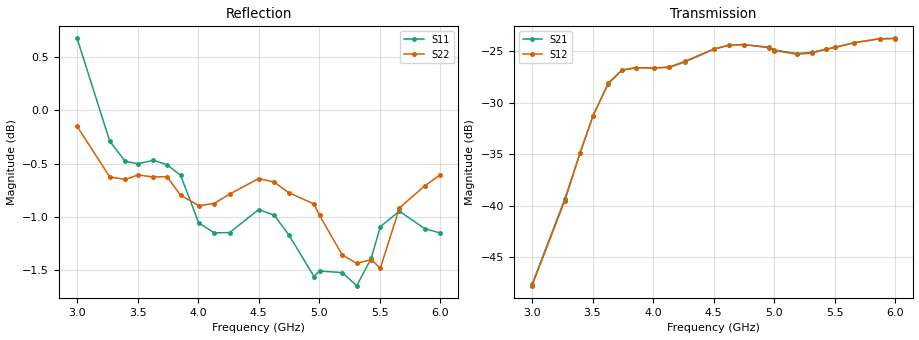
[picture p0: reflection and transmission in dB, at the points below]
!  26/11/2025  15:59:12
! Ref Plane: 0.000 mm
# MHZ S MA R  50
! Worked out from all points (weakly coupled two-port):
!   401 points, 3 GHz to 6 GHz, reference 50 ohm
!   highest |S21| = -23.72 dB at 6 GHz (marker M1); lowest = -47.7 dB at 3 GHz (marker M2)
!   lowest |S11| = -1.6 dB at 5.31 GHz (marker M3), VSWR 10.60, Z = 4.72 + j1.25 ohm
!   |S11| at or under -10 dB: nowhere
!   |S22| runs from -1.5 to -0.1 dB; largest |S21 - S12| = 0.0027
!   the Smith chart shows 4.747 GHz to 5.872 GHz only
!   S11 on the Smith chart (normalised r, x): 4.747 GHz: 2.45, -5.46; 4.957 GHz: 0.20, -1.09; 5.19 GHz: 0.09, -0.25; 5.43 GHz: 0.09, +0.35; 5.662 GHz: 0.14, +1.22; 5.872 GHz: 2.95, +6.06
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3000  1.081 -138.3  0.004127 48.7  0.00407 51.1  0.983 -106.4
3270  0.9673 151.7  0.01072 -17.9  0.01052 -15.1  0.9307 -170.9
3397.5  0.9466 108.7  0.01803 -57.9  0.01807 -56.8  0.9282 150.3
3502.5  0.9441 66.1  0.02723 -98.3  0.02715 -97.1  0.9327 112.4
3630  0.9476 10.9  0.03919 -154.4  0.03947 -153.0  0.9307 57.5
3742.5  0.9432 -39.2  0.0456 155.7  0.04556 157.3  0.931 9.7
3855  0.9324 -84.9  0.04684 109.7  0.04689 111.2  0.9125 -36.2
4005  0.8857 -138.8  0.04687 56.5  0.04668 57.7  0.9024 -88.4
4132.5  0.8762 178.3  0.04704 16.1  0.04719 18.1  0.9044 -127.2
4260  0.8765 140.4  0.04994 -22.2  0.05026 -20.2  0.9137 -167.7
4500  0.8985 64.1  0.05757 -96.8  0.05779 -95.3  0.9291 117.9
4627.5  0.8932 22.3  0.06041 -137.9  0.0603 -136.7  0.9256 78.6
4747.5  0.8746 -17.4  0.06073 -177.5  0.06074 -176.0  0.9151 40.3
4957.5  0.8358 -84.2  0.05902 118.5  0.0586 119.9  0.9039 -18.9
5002.5  0.8408 -98.7  0.05716 105.2  0.05677 106.5  0.893 -32.9
5190  0.8394 -151.9  0.05494 53.1  0.05453 54.2  0.8555 -86.3
5310  0.8276 177.1  0.05563 20.9  0.05519 22.4  0.8478 -122.9
5430  0.8525 141.4  0.05772 -11.0  0.05762 -8.9  0.8513 -152.8
5505  0.8821 120.9  0.05885 -31.1  0.05902 -29.1  0.8433 -175.3
5662.5  0.897 78.1  0.06207 -74.8  0.06202 -72.6  0.9001 142.0
5872.5  0.8801 15.3  0.06489 -136.6  0.06479 -134.8  0.9219 84.7
6000  0.8761 -20.8  0.06513 -172.6  0.06496 -170.9  0.9328 51.5
